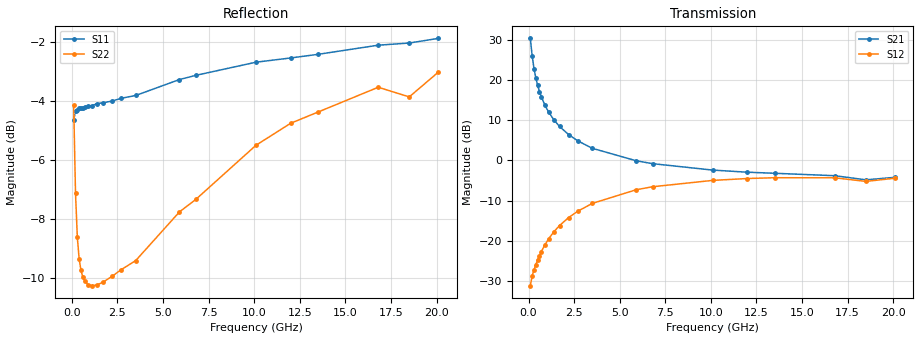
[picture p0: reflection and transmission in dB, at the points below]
!  Infineon Technologies AG
! BFR380L3 , PF131585-7, No.6, Th 09.10.01, soldered on pcb-board, measured with PP GSG850
!  Vce=0.5 V,  Ic=25.0 mA
! Common Emitter S-Parameters:  15. November 2001
#  GHz  S  MA  R  50
! f  S11  S21  S12  S22
! GHz  Mag  Ang  Mag  Ang  Mag  Ang  Mag  Ang
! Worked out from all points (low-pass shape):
!   201 points, 100 MHz to 20.1 GHz, reference 50 ohm
!   highest |S21| = 30.29 dB at 100 MHz (marker M1); lowest = -4.8 dB at 18.5 GHz (marker M2)
!   |S21| within 3 dB of the highest: start of sweep to 168.5 MHz
!   lowest |S11| = -4.7 dB at 100 MHz (marker M3), VSWR 3.82, Z = 19.8 - j33.9 ohm
!   |S11| at or under -10 dB: nowhere
!   |S22| runs from -10.3 to -3.0 dB; largest |S21 - S12| = 33
!   S11 on the Smith chart (normalised r, x): 100 MHz: 0.40, -0.68; 400 MHz: 0.25, -0.14; 2.2 GHz: 0.24, +0.23; 5.9 GHz: 0.28, +0.70; 12 GHz: 0.47, +1.44; 20.1 GHz: 0.92, +2.60
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0.1  0.5847 -105.8  32.71 127.9  0.02789 53.7  0.6196 -72.2
0.2  0.6065 -140.1  19.76 109.4  0.03686 48.7  0.4405 -106.0
0.3  0.6083 -154.6  13.82 101.1  0.04375 50.6  0.3708 -124.9
0.4  0.6123 -163.2  10.57 95.9  0.05065 53.7  0.3405 -137.1
0.5  0.6124 -168.9  8.538 92.0  0.05815 56.6  0.3259 -145.6
0.6  0.6131 -173.3  7.159 89.0  0.06581 58.5  0.3175 -151.9
0.7  0.6157 -176.9  6.173 86.3  0.07374 60.0  0.3129 -156.7
0.9  0.6188 177.3  4.836 81.8  0.08985 62.0  0.3079 -163.9
1.1  0.6188 172.5  3.994 77.9  0.1063 62.7  0.307 -169.0
1.4  0.6242 166.5  3.169 72.5  0.131 62.7  0.3081 -174.9
1.7  0.6259 161.2  2.638 67.5  0.1555 61.8  0.3112 -179.6
2.2  0.6301 152.8  2.091 60.0  0.1956 59.2  0.3183 174.2
2.7  0.637 145.3  1.75 52.9  0.2341 56.0  0.3267 168.7
3.5  0.644 134.3  1.413 42.7  0.293 50.2  0.3385 161.1
5.9  0.6853 107.2  0.9905 18.6  0.4322 32.3  0.4092 139.9
6.8  0.6966 98.8  0.9116 11.5  0.4713 25.6  0.4297 131.9
10.1  0.7332 75.3  0.7585 -8.1  0.5652 4.7  0.5306 108.6
12  0.7454 66.0  0.7142 -17.1  0.5963 -5.7  0.578 95.9
13.5  0.756 58.9  0.6926 -23.7  0.6099 -14.1  0.6038 87.0
16.8  0.7834 47.2  0.6458 -35.0  0.6081 -28.3  0.665 70.0
18.5  0.79 45.2  0.5743 -42.0  0.5489 -36.2  0.6405 65.9
20.1  0.8045 38.2  0.617 -45.5  0.6013 -40.8  0.7055 56.3
